VERSION 5.7 ;
  NOWIREEXTENSIONATPIN ON ;
  DIVIDERCHAR "/" ;
  BUSBITCHARS "[]" ;
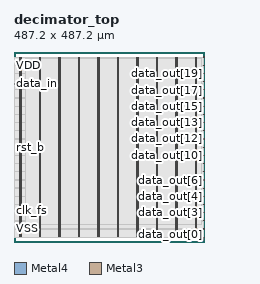
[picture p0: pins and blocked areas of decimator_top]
MACRO decimator_top
  CLASS BLOCK ;
  FOREIGN decimator_top ;
  ORIGIN 0.000 0.000 ;
  SIZE 487.200 BY 487.200 ;
  PIN VDD
    DIRECTION INOUT ;
    USE POWER ;
    PORT
      LAYER Metal4 ;
        RECT 14.540 13.280 15.540 473.920 ;
    END
    PORT
      LAYER Metal4 ;
        RECT 64.540 13.280 65.540 473.920 ;
    END
    PORT
      LAYER Metal4 ;
        RECT 114.540 13.280 115.540 473.920 ;
    END
    PORT
      LAYER Metal4 ;
        RECT 164.540 13.280 165.540 473.920 ;
    END
    PORT
      LAYER Metal4 ;
        RECT 214.540 13.280 215.540 473.920 ;
    END
    PORT
      LAYER Metal4 ;
        RECT 264.540 13.280 265.540 473.920 ;
    END
    PORT
      LAYER Metal4 ;
        RECT 314.540 13.280 315.540 473.920 ;
    END
    PORT
      LAYER Metal4 ;
        RECT 364.540 13.280 365.540 473.920 ;
    END
    PORT
      LAYER Metal4 ;
        RECT 414.540 13.280 415.540 473.920 ;
    END
    PORT
      LAYER Metal4 ;
        RECT 464.540 13.280 465.540 473.920 ;
    END
  END VDD
  PIN VSS
    DIRECTION INOUT ;
    USE GROUND ;
    PORT
      LAYER Metal4 ;
        RECT 17.540 13.280 18.540 473.920 ;
    END
    PORT
      LAYER Metal4 ;
        RECT 67.540 13.280 68.540 473.920 ;
    END
    PORT
      LAYER Metal4 ;
        RECT 117.540 13.280 118.540 473.920 ;
    END
    PORT
      LAYER Metal4 ;
        RECT 167.540 13.280 168.540 473.920 ;
    END
    PORT
      LAYER Metal4 ;
        RECT 217.540 13.280 218.540 473.920 ;
    END
    PORT
      LAYER Metal4 ;
        RECT 267.540 13.280 268.540 473.920 ;
    END
    PORT
      LAYER Metal4 ;
        RECT 317.540 13.280 318.540 473.920 ;
    END
    PORT
      LAYER Metal4 ;
        RECT 367.540 13.280 368.540 473.920 ;
    END
    PORT
      LAYER Metal4 ;
        RECT 417.540 13.280 418.540 473.920 ;
    END
    PORT
      LAYER Metal4 ;
        RECT 467.540 13.280 468.540 473.920 ;
    END
  END VSS
  PIN clk_fs
    DIRECTION INPUT ;
    USE SIGNAL ;
    ANTENNAGATEAREA 0.566800 ;
    PORT
      LAYER Metal3 ;
        RECT 0.000 80.860 0.400 81.260 ;
    END
  END clk_fs
  PIN data_in
    DIRECTION INPUT ;
    USE SIGNAL ;
    ANTENNAGATEAREA 0.101400 ;
    PORT
      LAYER Metal3 ;
        RECT 0.000 405.100 0.400 405.500 ;
    END
  END data_in
  PIN data_out[0]
    DIRECTION OUTPUT ;
    USE SIGNAL ;
    ANTENNADIFFAREA 0.741200 ;
    PORT
      LAYER Metal3 ;
        RECT 486.800 11.980 487.200 12.380 ;
    END
  END data_out[0]
  PIN data_out[10]
    DIRECTION OUTPUT ;
    USE SIGNAL ;
    ANTENNADIFFAREA 0.741200 ;
    PORT
      LAYER Metal3 ;
        RECT 486.800 221.980 487.200 222.380 ;
    END
  END data_out[10]
  PIN data_out[11]
    DIRECTION OUTPUT ;
    USE SIGNAL ;
    ANTENNADIFFAREA 0.741200 ;
    PORT
      LAYER Metal3 ;
        RECT 486.800 242.980 487.200 243.380 ;
    END
  END data_out[11]
  PIN data_out[12]
    DIRECTION OUTPUT ;
    USE SIGNAL ;
    ANTENNADIFFAREA 0.741200 ;
    PORT
      LAYER Metal3 ;
        RECT 486.800 263.980 487.200 264.380 ;
    END
  END data_out[12]
  PIN data_out[13]
    DIRECTION OUTPUT ;
    USE SIGNAL ;
    ANTENNADIFFAREA 0.741200 ;
    PORT
      LAYER Metal3 ;
        RECT 486.800 284.980 487.200 285.380 ;
    END
  END data_out[13]
  PIN data_out[14]
    DIRECTION OUTPUT ;
    USE SIGNAL ;
    ANTENNADIFFAREA 0.741200 ;
    PORT
      LAYER Metal3 ;
        RECT 486.800 305.980 487.200 306.380 ;
    END
  END data_out[14]
  PIN data_out[15]
    DIRECTION OUTPUT ;
    USE SIGNAL ;
    ANTENNADIFFAREA 0.741200 ;
    PORT
      LAYER Metal3 ;
        RECT 486.800 326.980 487.200 327.380 ;
    END
  END data_out[15]
  PIN data_out[16]
    DIRECTION OUTPUT ;
    USE SIGNAL ;
    ANTENNADIFFAREA 0.741200 ;
    PORT
      LAYER Metal3 ;
        RECT 486.800 347.980 487.200 348.380 ;
    END
  END data_out[16]
  PIN data_out[17]
    DIRECTION OUTPUT ;
    USE SIGNAL ;
    ANTENNADIFFAREA 0.741200 ;
    PORT
      LAYER Metal3 ;
        RECT 486.800 368.980 487.200 369.380 ;
    END
  END data_out[17]
  PIN data_out[18]
    DIRECTION OUTPUT ;
    USE SIGNAL ;
    ANTENNADIFFAREA 0.741200 ;
    PORT
      LAYER Metal3 ;
        RECT 486.800 389.980 487.200 390.380 ;
    END
  END data_out[18]
  PIN data_out[19]
    DIRECTION OUTPUT ;
    USE SIGNAL ;
    ANTENNADIFFAREA 0.741200 ;
    PORT
      LAYER Metal3 ;
        RECT 486.800 410.980 487.200 411.380 ;
    END
  END data_out[19]
  PIN data_out[1]
    DIRECTION OUTPUT ;
    USE SIGNAL ;
    ANTENNADIFFAREA 0.741200 ;
    PORT
      LAYER Metal3 ;
        RECT 486.800 32.980 487.200 33.380 ;
    END
  END data_out[1]
  PIN data_out[20]
    DIRECTION OUTPUT ;
    USE SIGNAL ;
    ANTENNADIFFAREA 0.741200 ;
    PORT
      LAYER Metal3 ;
        RECT 486.800 431.980 487.200 432.380 ;
    END
  END data_out[20]
  PIN data_out[21]
    DIRECTION OUTPUT ;
    USE SIGNAL ;
    ANTENNADIFFAREA 0.741200 ;
    PORT
      LAYER Metal3 ;
        RECT 486.800 452.980 487.200 453.380 ;
    END
  END data_out[21]
  PIN data_out[2]
    DIRECTION OUTPUT ;
    USE SIGNAL ;
    ANTENNADIFFAREA 0.741200 ;
    PORT
      LAYER Metal3 ;
        RECT 486.800 53.980 487.200 54.380 ;
    END
  END data_out[2]
  PIN data_out[3]
    DIRECTION OUTPUT ;
    USE SIGNAL ;
    ANTENNADIFFAREA 0.741200 ;
    PORT
      LAYER Metal3 ;
        RECT 486.800 74.980 487.200 75.380 ;
    END
  END data_out[3]
  PIN data_out[4]
    DIRECTION OUTPUT ;
    USE SIGNAL ;
    ANTENNADIFFAREA 0.741200 ;
    PORT
      LAYER Metal3 ;
        RECT 486.800 95.980 487.200 96.380 ;
    END
  END data_out[4]
  PIN data_out[5]
    DIRECTION OUTPUT ;
    USE SIGNAL ;
    ANTENNADIFFAREA 0.741200 ;
    PORT
      LAYER Metal3 ;
        RECT 486.800 116.980 487.200 117.380 ;
    END
  END data_out[5]
  PIN data_out[6]
    DIRECTION OUTPUT ;
    USE SIGNAL ;
    ANTENNADIFFAREA 0.741200 ;
    PORT
      LAYER Metal3 ;
        RECT 486.800 137.980 487.200 138.380 ;
    END
  END data_out[6]
  PIN data_out[7]
    DIRECTION OUTPUT ;
    USE SIGNAL ;
    ANTENNADIFFAREA 0.741200 ;
    PORT
      LAYER Metal3 ;
        RECT 486.800 158.980 487.200 159.380 ;
    END
  END data_out[7]
  PIN data_out[8]
    DIRECTION OUTPUT ;
    USE SIGNAL ;
    ANTENNADIFFAREA 0.741200 ;
    PORT
      LAYER Metal3 ;
        RECT 486.800 179.980 487.200 180.380 ;
    END
  END data_out[8]
  PIN data_out[9]
    DIRECTION OUTPUT ;
    USE SIGNAL ;
    ANTENNADIFFAREA 0.741200 ;
    PORT
      LAYER Metal3 ;
        RECT 486.800 200.980 487.200 201.380 ;
    END
  END data_out[9]
  PIN rst_b
    DIRECTION INPUT ;
    USE SIGNAL ;
    ANTENNAGATEAREA 0.101400 ;
    PORT
      LAYER Metal3 ;
        RECT 0.000 242.980 0.400 243.380 ;
    END
  END rst_b
  PIN valid_strobe
    DIRECTION OUTPUT ;
    USE SIGNAL ;
    ANTENNADIFFAREA 0.741200 ;
    PORT
      LAYER Metal3 ;
        RECT 486.800 473.980 487.200 474.380 ;
    END
  END valid_strobe
  OBS
      LAYER GatPoly ;
        RECT 5.165 13.530 482.055 473.670 ;
      LAYER Metal1 ;
        RECT 5.040 13.280 482.160 473.920 ;
      LAYER Metal2 ;
        RECT 5.150 12.035 484.150 474.325 ;
      LAYER Metal3 ;
        RECT 0.400 473.770 486.590 474.280 ;
        RECT 0.400 453.590 486.800 473.770 ;
        RECT 0.400 452.770 486.590 453.590 ;
        RECT 0.400 432.590 486.800 452.770 ;
        RECT 0.400 431.770 486.590 432.590 ;
        RECT 0.400 411.590 486.800 431.770 ;
        RECT 0.400 410.770 486.590 411.590 ;
        RECT 0.400 405.710 486.800 410.770 ;
        RECT 0.610 404.890 486.800 405.710 ;
        RECT 0.400 390.590 486.800 404.890 ;
        RECT 0.400 389.770 486.590 390.590 ;
        RECT 0.400 369.590 486.800 389.770 ;
        RECT 0.400 368.770 486.590 369.590 ;
        RECT 0.400 348.590 486.800 368.770 ;
        RECT 0.400 347.770 486.590 348.590 ;
        RECT 0.400 327.590 486.800 347.770 ;
        RECT 0.400 326.770 486.590 327.590 ;
        RECT 0.400 306.590 486.800 326.770 ;
        RECT 0.400 305.770 486.590 306.590 ;
        RECT 0.400 285.590 486.800 305.770 ;
        RECT 0.400 284.770 486.590 285.590 ;
        RECT 0.400 264.590 486.800 284.770 ;
        RECT 0.400 263.770 486.590 264.590 ;
        RECT 0.400 243.590 486.800 263.770 ;
        RECT 0.610 242.770 486.590 243.590 ;
        RECT 0.400 222.590 486.800 242.770 ;
        RECT 0.400 221.770 486.590 222.590 ;
        RECT 0.400 201.590 486.800 221.770 ;
        RECT 0.400 200.770 486.590 201.590 ;
        RECT 0.400 180.590 486.800 200.770 ;
        RECT 0.400 179.770 486.590 180.590 ;
        RECT 0.400 159.590 486.800 179.770 ;
        RECT 0.400 158.770 486.590 159.590 ;
        RECT 0.400 138.590 486.800 158.770 ;
        RECT 0.400 137.770 486.590 138.590 ;
        RECT 0.400 117.590 486.800 137.770 ;
        RECT 0.400 116.770 486.590 117.590 ;
        RECT 0.400 96.590 486.800 116.770 ;
        RECT 0.400 95.770 486.590 96.590 ;
        RECT 0.400 81.470 486.800 95.770 ;
        RECT 0.610 80.650 486.800 81.470 ;
        RECT 0.400 75.590 486.800 80.650 ;
        RECT 0.400 74.770 486.590 75.590 ;
        RECT 0.400 54.590 486.800 74.770 ;
        RECT 0.400 53.770 486.590 54.590 ;
        RECT 0.400 33.590 486.800 53.770 ;
        RECT 0.400 32.770 486.590 33.590 ;
        RECT 0.400 12.590 486.800 32.770 ;
        RECT 0.400 12.080 486.590 12.590 ;
      LAYER Metal4 ;
        RECT 30.350 45.635 64.330 469.285 ;
        RECT 65.750 45.635 67.330 469.285 ;
        RECT 68.750 45.635 114.330 469.285 ;
        RECT 115.750 45.635 117.330 469.285 ;
        RECT 118.750 45.635 164.330 469.285 ;
        RECT 165.750 45.635 167.330 469.285 ;
        RECT 168.750 45.635 214.330 469.285 ;
        RECT 215.750 45.635 217.330 469.285 ;
        RECT 218.750 45.635 264.330 469.285 ;
        RECT 265.750 45.635 267.330 469.285 ;
        RECT 268.750 45.635 314.330 469.285 ;
        RECT 315.750 45.635 317.330 469.285 ;
        RECT 318.750 45.635 364.330 469.285 ;
        RECT 365.750 45.635 367.330 469.285 ;
        RECT 368.750 45.635 414.330 469.285 ;
        RECT 415.750 45.635 417.330 469.285 ;
        RECT 418.750 45.635 464.330 469.285 ;
        RECT 465.750 45.635 467.330 469.285 ;
        RECT 468.750 45.635 481.630 469.285 ;
  END
END decimator_top
END LIBRARY

